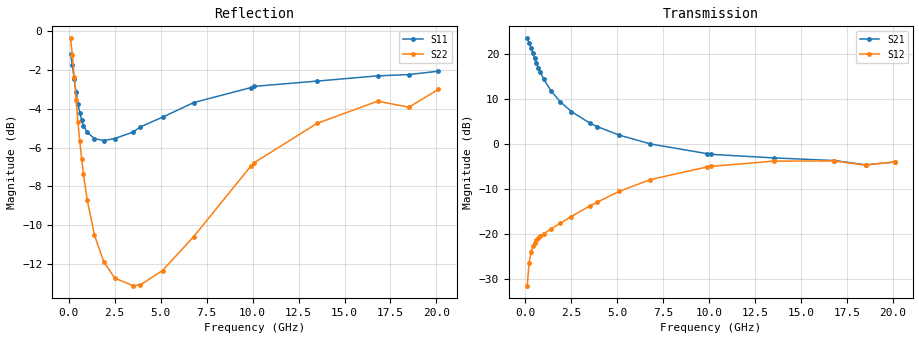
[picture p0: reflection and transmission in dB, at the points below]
!  Infineon Technologies AG
! BFR380L3 , PF131585-7, No.6, Th 09.10.01, soldered on pcb-board, measured with PP GSG850
!  Vce=5.0 V,  Ic=5.0 mA
! Common Emitter S-Parameters:  15. November 2001
#  GHz  S  MA  R  50
! f  S11  S21  S12  S22
! GHz  Mag  Ang  Mag  Ang  Mag  Ang  Mag  Ang
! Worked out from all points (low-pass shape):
!   201 points, 100 MHz to 20.1 GHz, reference 50 ohm
!   highest |S21| = 23.48 dB at 100 MHz (marker M1); lowest = -4.7 dB at 18.5 GHz (marker M2)
!   |S21| within 3 dB of the highest: start of sweep to 379.3 MHz
!   lowest |S11| = -5.6 dB at 1.9 GHz (marker M3), VSWR 3.19, Z = 15.7 - j1.19 ohm
!   |S11| at or under -10 dB: nowhere
!   |S22| runs from -13.1 to -0.4 dB; largest |S21 - S12| = 15
!   S11 on the Smith chart (normalised r, x): 100 MHz: 1.25, -4.00; 400 MHz: 0.38, -1.01; 1 GHz: 0.32, -0.32; 3.9 GHz: 0.31, +0.31; 9.9 GHz: 0.39, +1.12; 20.1 GHz: 0.97, +2.51
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0.1  0.873 -25.8  14.94 162.5  0.02647 74.6  0.9557 -15.2
0.2  0.8145 -48.7  13.43 147.4  0.04713 64.9  0.8644 -28.2
0.3  0.7511 -69.1  11.8 135.1  0.06202 56.5  0.7592 -38.2
0.4  0.694 -85.4  10.27 125.3  0.07251 50.7  0.6628 -45.5
0.5  0.6501 -98.8  8.971 117.6  0.07965 47.1  0.584 -50.8
0.6  0.6157 -110.2  7.896 111.5  0.08526 44.7  0.52 -54.8
0.7  0.5905 -119.9  7.035 106.2  0.08964 43.2  0.4688 -57.8
0.8  0.5708 -128.1  6.313 101.7  0.0935 42.5  0.4283 -60.2
1  0.5484 -141.2  5.227 94.5  0.1003 42.0  0.3683 -63.8
1.4  0.5283 -160.4  3.875 83.4  0.1135 43.6  0.2985 -69.1
1.9  0.5224 -177.0  2.941 72.5  0.1311 46.6  0.2553 -75.1
2.5  0.5285 168.1  2.293 61.8  0.1557 49.3  0.2316 -83.5
3.5  0.5493 149.0  1.706 46.6  0.2043 51.3  0.2214 -100.2
3.9  0.5665 142.7  1.561 41.4  0.2245 51.2  0.2225 -108.7
5.1  0.5996 125.9  1.254 27.1  0.2967 47.9  0.2422 -132.2
6.8  0.6539 105.8  1 11.6  0.4012 39.2  0.2961 -166.6
9.9  0.7141 79.5  0.7773 -6.4  0.5555 17.8  0.4487 145.9
10.1  0.7196 78.0  0.7662 -7.2  0.5629 16.4  0.4585 143.2
13.5  0.7423 59.6  0.6989 -20.7  0.6438 -6.7  0.5778 106.8
16.8  0.7657 47.7  0.6532 -32.0  0.6459 -24.0  0.6593 81.6
18.5  0.7716 45.9  0.5852 -39.3  0.5802 -32.6  0.636 75.0
20.1  0.787 38.8  0.6293 -42.9  0.6342 -38.0  0.7068 63.8
